VERSION 5.7 ;
  NOWIREEXTENSIONATPIN ON ;
  DIVIDERCHAR "/" ;
  BUSBITCHARS "[]" ;
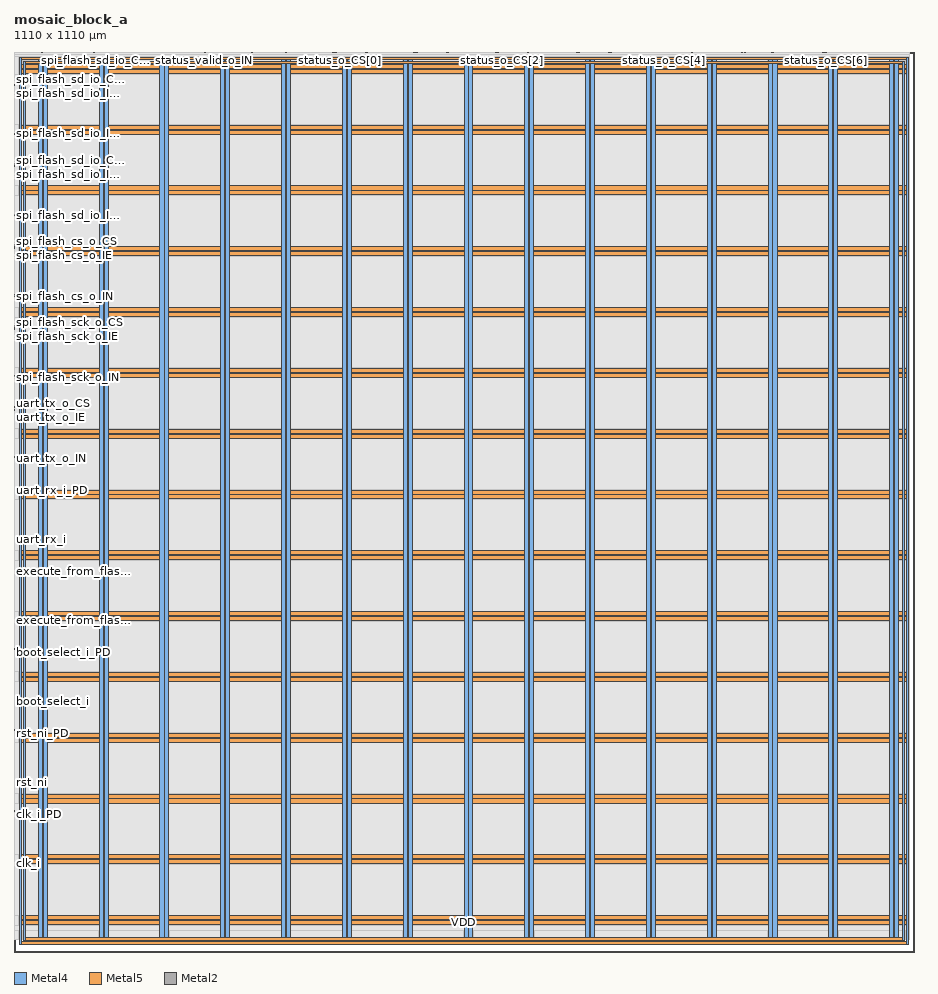
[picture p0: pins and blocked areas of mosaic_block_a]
MACRO mosaic_block_a
  CLASS BLOCK ;
  FOREIGN mosaic_block_a ;
  ORIGIN 0.000 0.000 ;
  SIZE 1110.000 BY 1110.000 ;
  PIN VDD
    DIRECTION INOUT ;
    USE POWER ;
    PORT
      LAYER Metal4 ;
        RECT 11.240 14.600 14.240 1098.680 ;
    END
    PORT
      LAYER Metal4 ;
        RECT 1095.680 14.600 1098.680 1098.680 ;
    END
    PORT
      LAYER Metal5 ;
        RECT 11.240 14.600 1098.680 17.600 ;
    END
    PORT
      LAYER Metal5 ;
        RECT 11.240 1095.680 1098.680 1098.680 ;
    END
    PORT
      LAYER Metal4 ;
        RECT 30.060 9.600 35.060 1103.680 ;
    END
    PORT
      LAYER Metal4 ;
        RECT 105.060 9.600 110.060 1103.680 ;
    END
    PORT
      LAYER Metal4 ;
        RECT 180.060 9.600 185.060 1103.680 ;
    END
    PORT
      LAYER Metal4 ;
        RECT 255.060 9.600 260.060 1103.680 ;
    END
    PORT
      LAYER Metal4 ;
        RECT 330.060 9.600 335.060 1103.680 ;
    END
    PORT
      LAYER Metal4 ;
        RECT 405.060 9.600 410.060 1103.680 ;
    END
    PORT
      LAYER Metal4 ;
        RECT 480.060 9.600 485.060 1103.680 ;
    END
    PORT
      LAYER Metal4 ;
        RECT 555.060 9.600 560.060 1103.680 ;
    END
    PORT
      LAYER Metal4 ;
        RECT 630.060 9.600 635.060 1103.680 ;
    END
    PORT
      LAYER Metal4 ;
        RECT 705.060 9.600 710.060 1103.680 ;
    END
    PORT
      LAYER Metal4 ;
        RECT 780.060 9.600 785.060 1103.680 ;
    END
    PORT
      LAYER Metal4 ;
        RECT 855.060 9.600 860.060 1103.680 ;
    END
    PORT
      LAYER Metal4 ;
        RECT 930.060 9.600 935.060 1103.680 ;
    END
    PORT
      LAYER Metal4 ;
        RECT 1005.060 9.600 1010.060 1103.680 ;
    END
    PORT
      LAYER Metal4 ;
        RECT 1080.060 9.600 1085.060 1103.680 ;
    END
    PORT
      LAYER Metal5 ;
        RECT 6.240 33.750 1103.680 38.750 ;
    END
    PORT
      LAYER Metal5 ;
        RECT 6.240 108.750 1103.680 113.750 ;
    END
    PORT
      LAYER Metal5 ;
        RECT 6.240 183.750 1103.680 188.750 ;
    END
    PORT
      LAYER Metal5 ;
        RECT 6.240 258.750 1103.680 263.750 ;
    END
    PORT
      LAYER Metal5 ;
        RECT 6.240 333.750 1103.680 338.750 ;
    END
    PORT
      LAYER Metal5 ;
        RECT 6.240 408.750 1103.680 413.750 ;
    END
    PORT
      LAYER Metal5 ;
        RECT 6.240 483.750 1103.680 488.750 ;
    END
    PORT
      LAYER Metal5 ;
        RECT 6.240 558.750 1103.680 563.750 ;
    END
    PORT
      LAYER Metal5 ;
        RECT 6.240 633.750 1103.680 638.750 ;
    END
    PORT
      LAYER Metal5 ;
        RECT 6.240 708.750 1103.680 713.750 ;
    END
    PORT
      LAYER Metal5 ;
        RECT 6.240 783.750 1103.680 788.750 ;
    END
    PORT
      LAYER Metal5 ;
        RECT 6.240 858.750 1103.680 863.750 ;
    END
    PORT
      LAYER Metal5 ;
        RECT 6.240 933.750 1103.680 938.750 ;
    END
    PORT
      LAYER Metal5 ;
        RECT 6.240 1008.750 1103.680 1013.750 ;
    END
    PORT
      LAYER Metal5 ;
        RECT 6.240 1083.750 1103.680 1088.750 ;
    END
  END VDD
  PIN VSS
    DIRECTION INOUT ;
    USE GROUND ;
    PORT
      LAYER Metal4 ;
        RECT 6.240 9.600 9.240 1103.680 ;
    END
    PORT
      LAYER Metal4 ;
        RECT 1100.680 9.600 1103.680 1103.680 ;
    END
    PORT
      LAYER Metal5 ;
        RECT 6.240 9.600 1103.680 12.600 ;
    END
    PORT
      LAYER Metal5 ;
        RECT 6.240 1100.680 1103.680 1103.680 ;
    END
    PORT
      LAYER Metal4 ;
        RECT 36.060 9.600 41.060 1103.680 ;
    END
    PORT
      LAYER Metal4 ;
        RECT 111.060 9.600 116.060 1103.680 ;
    END
    PORT
      LAYER Metal4 ;
        RECT 186.060 9.600 191.060 1103.680 ;
    END
    PORT
      LAYER Metal4 ;
        RECT 261.060 9.600 266.060 1103.680 ;
    END
    PORT
      LAYER Metal4 ;
        RECT 336.060 9.600 341.060 1103.680 ;
    END
    PORT
      LAYER Metal4 ;
        RECT 411.060 9.600 416.060 1103.680 ;
    END
    PORT
      LAYER Metal4 ;
        RECT 486.060 9.600 491.060 1103.680 ;
    END
    PORT
      LAYER Metal4 ;
        RECT 561.060 9.600 566.060 1103.680 ;
    END
    PORT
      LAYER Metal4 ;
        RECT 636.060 9.600 641.060 1103.680 ;
    END
    PORT
      LAYER Metal4 ;
        RECT 711.060 9.600 716.060 1103.680 ;
    END
    PORT
      LAYER Metal4 ;
        RECT 786.060 9.600 791.060 1103.680 ;
    END
    PORT
      LAYER Metal4 ;
        RECT 861.060 9.600 866.060 1103.680 ;
    END
    PORT
      LAYER Metal4 ;
        RECT 936.060 9.600 941.060 1103.680 ;
    END
    PORT
      LAYER Metal4 ;
        RECT 1011.060 9.600 1016.060 1103.680 ;
    END
    PORT
      LAYER Metal4 ;
        RECT 1086.060 9.600 1091.060 1103.680 ;
    END
    PORT
      LAYER Metal5 ;
        RECT 6.240 39.750 1103.680 44.750 ;
    END
    PORT
      LAYER Metal5 ;
        RECT 6.240 114.750 1103.680 119.750 ;
    END
    PORT
      LAYER Metal5 ;
        RECT 6.240 189.750 1103.680 194.750 ;
    END
    PORT
      LAYER Metal5 ;
        RECT 6.240 264.750 1103.680 269.750 ;
    END
    PORT
      LAYER Metal5 ;
        RECT 6.240 339.750 1103.680 344.750 ;
    END
    PORT
      LAYER Metal5 ;
        RECT 6.240 414.750 1103.680 419.750 ;
    END
    PORT
      LAYER Metal5 ;
        RECT 6.240 489.750 1103.680 494.750 ;
    END
    PORT
      LAYER Metal5 ;
        RECT 6.240 564.750 1103.680 569.750 ;
    END
    PORT
      LAYER Metal5 ;
        RECT 6.240 639.750 1103.680 644.750 ;
    END
    PORT
      LAYER Metal5 ;
        RECT 6.240 714.750 1103.680 719.750 ;
    END
    PORT
      LAYER Metal5 ;
        RECT 6.240 789.750 1103.680 794.750 ;
    END
    PORT
      LAYER Metal5 ;
        RECT 6.240 864.750 1103.680 869.750 ;
    END
    PORT
      LAYER Metal5 ;
        RECT 6.240 939.750 1103.680 944.750 ;
    END
    PORT
      LAYER Metal5 ;
        RECT 6.240 1014.750 1103.680 1019.750 ;
    END
    PORT
      LAYER Metal5 ;
        RECT 6.240 1089.750 1103.680 1094.750 ;
    END
  END VSS
  PIN boot_select_i
    DIRECTION INPUT ;
    USE SIGNAL ;
    ANTENNAGATEAREA 0.396000 ;
    PORT
      LAYER Metal2 ;
        RECT 0.000 308.760 1.000 309.140 ;
    END
  END boot_select_i
  PIN boot_select_i_PD
    DIRECTION OUTPUT ;
    USE SIGNAL ;
    ANTENNADIFFAREA 0.360800 ;
    PORT
      LAYER Metal2 ;
        RECT 0.000 369.290 1.000 369.670 ;
    END
  END boot_select_i_PD
  PIN boot_select_i_PU
    DIRECTION OUTPUT ;
    USE SIGNAL ;
    ANTENNADIFFAREA 0.360800 ;
    PORT
      LAYER Metal2 ;
        RECT 0.000 373.655 1.000 374.035 ;
    END
  END boot_select_i_PU
  PIN clk_i
    DIRECTION INPUT ;
    USE SIGNAL ;
    ANTENNAGATEAREA 9.476000 ;
    PORT
      LAYER Metal2 ;
        RECT 0.000 108.760 1.000 109.140 ;
    END
  END clk_i
  PIN clk_i_PD
    DIRECTION OUTPUT ;
    USE SIGNAL ;
    ANTENNADIFFAREA 0.360800 ;
    PORT
      LAYER Metal2 ;
        RECT 0.000 169.290 1.000 169.670 ;
    END
  END clk_i_PD
  PIN clk_i_PU
    DIRECTION OUTPUT ;
    USE SIGNAL ;
    ANTENNADIFFAREA 0.360800 ;
    PORT
      LAYER Metal2 ;
        RECT 0.000 173.655 1.000 174.035 ;
    END
  END clk_i_PU
  PIN execute_from_flash_i
    DIRECTION INPUT ;
    USE SIGNAL ;
    ANTENNAGATEAREA 0.498500 ;
    PORT
      LAYER Metal2 ;
        RECT 0.000 408.760 1.000 409.140 ;
    END
  END execute_from_flash_i
  PIN execute_from_flash_i_PD
    DIRECTION OUTPUT ;
    USE SIGNAL ;
    ANTENNADIFFAREA 0.360800 ;
    PORT
      LAYER Metal2 ;
        RECT 0.000 469.290 1.000 469.670 ;
    END
  END execute_from_flash_i_PD
  PIN execute_from_flash_i_PU
    DIRECTION OUTPUT ;
    USE SIGNAL ;
    ANTENNADIFFAREA 0.360800 ;
    PORT
      LAYER Metal2 ;
        RECT 0.000 473.655 1.000 474.035 ;
    END
  END execute_from_flash_i_PU
  PIN rst_ni
    DIRECTION INPUT ;
    USE SIGNAL ;
    ANTENNAGATEAREA 0.396000 ;
    PORT
      LAYER Metal2 ;
        RECT 0.000 208.760 1.000 209.140 ;
    END
  END rst_ni
  PIN rst_ni_PD
    DIRECTION OUTPUT ;
    USE SIGNAL ;
    ANTENNADIFFAREA 0.536800 ;
    PORT
      LAYER Metal2 ;
        RECT 0.000 269.290 1.000 269.670 ;
    END
  END rst_ni_PD
  PIN rst_ni_PU
    DIRECTION OUTPUT ;
    USE SIGNAL ;
    ANTENNADIFFAREA 0.360800 ;
    PORT
      LAYER Metal2 ;
        RECT 0.000 273.655 1.000 274.035 ;
    END
  END rst_ni_PU
  PIN spi_flash_cs_o_CS
    DIRECTION OUTPUT ;
    USE SIGNAL ;
    ANTENNADIFFAREA 0.360800 ;
    PORT
      LAYER Metal2 ;
        RECT 0.000 876.260 1.000 876.640 ;
    END
  END spi_flash_cs_o_CS
  PIN spi_flash_cs_o_IE
    DIRECTION OUTPUT ;
    USE SIGNAL ;
    ANTENNADIFFAREA 0.360800 ;
    PORT
      LAYER Metal2 ;
        RECT 0.000 868.235 1.000 868.615 ;
    END
  END spi_flash_cs_o_IE
  PIN spi_flash_cs_o_IN
    DIRECTION INPUT ;
    USE SIGNAL ;
    PORT
      LAYER Metal2 ;
        RECT 0.000 808.760 1.000 809.140 ;
    END
  END spi_flash_cs_o_IN
  PIN spi_flash_cs_o_OE
    DIRECTION OUTPUT ;
    USE SIGNAL ;
    ANTENNADIFFAREA 0.536800 ;
    PORT
      LAYER Metal2 ;
        RECT 0.000 809.490 1.000 809.870 ;
    END
  END spi_flash_cs_o_OE
  PIN spi_flash_cs_o_OUT
    DIRECTION OUTPUT ;
    USE SIGNAL ;
    ANTENNADIFFAREA 0.897600 ;
    PORT
      LAYER Metal2 ;
        RECT 0.000 810.220 1.000 810.600 ;
    END
  END spi_flash_cs_o_OUT
  PIN spi_flash_cs_o_PD
    DIRECTION OUTPUT ;
    USE SIGNAL ;
    ANTENNADIFFAREA 0.360800 ;
    PORT
      LAYER Metal2 ;
        RECT 0.000 869.290 1.000 869.670 ;
    END
  END spi_flash_cs_o_PD
  PIN spi_flash_cs_o_PDRV0
    DIRECTION OUTPUT ;
    USE SIGNAL ;
    ANTENNADIFFAREA 0.360800 ;
    PORT
      LAYER Metal2 ;
        RECT 0.000 872.510 1.000 872.890 ;
    END
  END spi_flash_cs_o_PDRV0
  PIN spi_flash_cs_o_PDRV1
    DIRECTION OUTPUT ;
    USE SIGNAL ;
    ANTENNADIFFAREA 0.536800 ;
    PORT
      LAYER Metal2 ;
        RECT 0.000 871.800 1.000 872.180 ;
    END
  END spi_flash_cs_o_PDRV1
  PIN spi_flash_cs_o_PU
    DIRECTION OUTPUT ;
    USE SIGNAL ;
    ANTENNADIFFAREA 0.360800 ;
    PORT
      LAYER Metal2 ;
        RECT 0.000 873.655 1.000 874.035 ;
    END
  END spi_flash_cs_o_PU
  PIN spi_flash_cs_o_SL
    DIRECTION OUTPUT ;
    USE SIGNAL ;
    ANTENNADIFFAREA 0.360800 ;
    PORT
      LAYER Metal2 ;
        RECT 0.000 810.950 1.000 811.330 ;
    END
  END spi_flash_cs_o_SL
  PIN spi_flash_sck_o_CS
    DIRECTION OUTPUT ;
    USE SIGNAL ;
    ANTENNADIFFAREA 0.360800 ;
    PORT
      LAYER Metal2 ;
        RECT 0.000 776.260 1.000 776.640 ;
    END
  END spi_flash_sck_o_CS
  PIN spi_flash_sck_o_IE
    DIRECTION OUTPUT ;
    USE SIGNAL ;
    ANTENNADIFFAREA 0.360800 ;
    PORT
      LAYER Metal2 ;
        RECT 0.000 768.235 1.000 768.615 ;
    END
  END spi_flash_sck_o_IE
  PIN spi_flash_sck_o_IN
    DIRECTION INPUT ;
    USE SIGNAL ;
    PORT
      LAYER Metal2 ;
        RECT 0.000 708.760 1.000 709.140 ;
    END
  END spi_flash_sck_o_IN
  PIN spi_flash_sck_o_OE
    DIRECTION OUTPUT ;
    USE SIGNAL ;
    ANTENNADIFFAREA 0.536800 ;
    PORT
      LAYER Metal2 ;
        RECT 0.000 709.490 1.000 709.870 ;
    END
  END spi_flash_sck_o_OE
  PIN spi_flash_sck_o_OUT
    DIRECTION OUTPUT ;
    USE SIGNAL ;
    ANTENNADIFFAREA 0.897600 ;
    PORT
      LAYER Metal2 ;
        RECT 0.000 710.220 1.000 710.600 ;
    END
  END spi_flash_sck_o_OUT
  PIN spi_flash_sck_o_PD
    DIRECTION OUTPUT ;
    USE SIGNAL ;
    ANTENNADIFFAREA 0.360800 ;
    PORT
      LAYER Metal2 ;
        RECT 0.000 769.290 1.000 769.670 ;
    END
  END spi_flash_sck_o_PD
  PIN spi_flash_sck_o_PDRV0
    DIRECTION OUTPUT ;
    USE SIGNAL ;
    ANTENNADIFFAREA 0.360800 ;
    PORT
      LAYER Metal2 ;
        RECT 0.000 772.510 1.000 772.890 ;
    END
  END spi_flash_sck_o_PDRV0
  PIN spi_flash_sck_o_PDRV1
    DIRECTION OUTPUT ;
    USE SIGNAL ;
    ANTENNADIFFAREA 0.536800 ;
    PORT
      LAYER Metal2 ;
        RECT 0.000 771.800 1.000 772.180 ;
    END
  END spi_flash_sck_o_PDRV1
  PIN spi_flash_sck_o_PU
    DIRECTION OUTPUT ;
    USE SIGNAL ;
    ANTENNADIFFAREA 0.360800 ;
    PORT
      LAYER Metal2 ;
        RECT 0.000 773.655 1.000 774.035 ;
    END
  END spi_flash_sck_o_PU
  PIN spi_flash_sck_o_SL
    DIRECTION OUTPUT ;
    USE SIGNAL ;
    ANTENNADIFFAREA 0.360800 ;
    PORT
      LAYER Metal2 ;
        RECT 0.000 710.950 1.000 711.330 ;
    END
  END spi_flash_sck_o_SL
  PIN spi_flash_sd_io_CS[0]
    DIRECTION OUTPUT ;
    USE SIGNAL ;
    ANTENNADIFFAREA 0.360800 ;
    PORT
      LAYER Metal2 ;
        RECT 0.000 976.260 1.000 976.640 ;
    END
  END spi_flash_sd_io_CS[0]
  PIN spi_flash_sd_io_CS[1]
    DIRECTION OUTPUT ;
    USE SIGNAL ;
    ANTENNADIFFAREA 0.360800 ;
    PORT
      LAYER Metal2 ;
        RECT 0.000 1076.260 1.000 1076.640 ;
    END
  END spi_flash_sd_io_CS[1]
  PIN spi_flash_sd_io_CS[2]
    DIRECTION OUTPUT ;
    USE SIGNAL ;
    ANTENNADIFFAREA 0.360800 ;
    PORT
      LAYER Metal2 ;
        RECT 101.260 1109.000 101.640 1110.000 ;
    END
  END spi_flash_sd_io_CS[2]
  PIN spi_flash_sd_io_CS[3]
    DIRECTION OUTPUT ;
    USE SIGNAL ;
    ANTENNADIFFAREA 0.360800 ;
    PORT
      LAYER Metal2 ;
        RECT 201.260 1109.000 201.640 1110.000 ;
    END
  END spi_flash_sd_io_CS[3]
  PIN spi_flash_sd_io_IE[0]
    DIRECTION OUTPUT ;
    USE SIGNAL ;
    ANTENNADIFFAREA 0.897600 ;
    PORT
      LAYER Metal2 ;
        RECT 0.000 968.235 1.000 968.615 ;
    END
  END spi_flash_sd_io_IE[0]
  PIN spi_flash_sd_io_IE[1]
    DIRECTION OUTPUT ;
    USE SIGNAL ;
    ANTENNADIFFAREA 0.897600 ;
    PORT
      LAYER Metal2 ;
        RECT 0.000 1068.235 1.000 1068.615 ;
    END
  END spi_flash_sd_io_IE[1]
  PIN spi_flash_sd_io_IE[2]
    DIRECTION OUTPUT ;
    USE SIGNAL ;
    ANTENNADIFFAREA 0.897600 ;
    PORT
      LAYER Metal2 ;
        RECT 93.235 1109.000 93.615 1110.000 ;
    END
  END spi_flash_sd_io_IE[2]
  PIN spi_flash_sd_io_IE[3]
    DIRECTION OUTPUT ;
    USE SIGNAL ;
    ANTENNADIFFAREA 0.897600 ;
    PORT
      LAYER Metal2 ;
        RECT 193.235 1109.000 193.615 1110.000 ;
    END
  END spi_flash_sd_io_IE[3]
  PIN spi_flash_sd_io_IN[0]
    DIRECTION INPUT ;
    USE SIGNAL ;
    ANTENNAGATEAREA 0.396000 ;
    PORT
      LAYER Metal2 ;
        RECT 0.000 908.760 1.000 909.140 ;
    END
  END spi_flash_sd_io_IN[0]
  PIN spi_flash_sd_io_IN[1]
    DIRECTION INPUT ;
    USE SIGNAL ;
    ANTENNAGATEAREA 0.498500 ;
    PORT
      LAYER Metal2 ;
        RECT 0.000 1008.760 1.000 1009.140 ;
    END
  END spi_flash_sd_io_IN[1]
  PIN spi_flash_sd_io_IN[2]
    DIRECTION INPUT ;
    USE SIGNAL ;
    ANTENNAGATEAREA 0.396000 ;
    PORT
      LAYER Metal2 ;
        RECT 33.760 1109.000 34.140 1110.000 ;
    END
  END spi_flash_sd_io_IN[2]
  PIN spi_flash_sd_io_IN[3]
    DIRECTION INPUT ;
    USE SIGNAL ;
    ANTENNAGATEAREA 0.396000 ;
    PORT
      LAYER Metal2 ;
        RECT 133.760 1109.000 134.140 1110.000 ;
    END
  END spi_flash_sd_io_IN[3]
  PIN spi_flash_sd_io_OE[0]
    DIRECTION OUTPUT ;
    USE SIGNAL ;
    ANTENNADIFFAREA 0.897600 ;
    PORT
      LAYER Metal2 ;
        RECT 0.000 909.490 1.000 909.870 ;
    END
  END spi_flash_sd_io_OE[0]
  PIN spi_flash_sd_io_OE[1]
    DIRECTION OUTPUT ;
    USE SIGNAL ;
    ANTENNADIFFAREA 0.897600 ;
    PORT
      LAYER Metal2 ;
        RECT 0.000 1009.490 1.000 1009.870 ;
    END
  END spi_flash_sd_io_OE[1]
  PIN spi_flash_sd_io_OE[2]
    DIRECTION OUTPUT ;
    USE SIGNAL ;
    ANTENNADIFFAREA 0.897600 ;
    PORT
      LAYER Metal2 ;
        RECT 34.490 1109.000 34.870 1110.000 ;
    END
  END spi_flash_sd_io_OE[2]
  PIN spi_flash_sd_io_OE[3]
    DIRECTION OUTPUT ;
    USE SIGNAL ;
    ANTENNADIFFAREA 0.897600 ;
    PORT
      LAYER Metal2 ;
        RECT 134.490 1109.000 134.870 1110.000 ;
    END
  END spi_flash_sd_io_OE[3]
  PIN spi_flash_sd_io_OUT[0]
    DIRECTION OUTPUT ;
    USE SIGNAL ;
    ANTENNADIFFAREA 0.897600 ;
    PORT
      LAYER Metal2 ;
        RECT 0.000 910.220 1.000 910.600 ;
    END
  END spi_flash_sd_io_OUT[0]
  PIN spi_flash_sd_io_OUT[1]
    DIRECTION OUTPUT ;
    USE SIGNAL ;
    ANTENNADIFFAREA 0.897600 ;
    PORT
      LAYER Metal2 ;
        RECT 0.000 1010.220 1.000 1010.600 ;
    END
  END spi_flash_sd_io_OUT[1]
  PIN spi_flash_sd_io_OUT[2]
    DIRECTION OUTPUT ;
    USE SIGNAL ;
    ANTENNADIFFAREA 0.897600 ;
    PORT
      LAYER Metal2 ;
        RECT 35.220 1109.000 35.600 1110.000 ;
    END
  END spi_flash_sd_io_OUT[2]
  PIN spi_flash_sd_io_OUT[3]
    DIRECTION OUTPUT ;
    USE SIGNAL ;
    ANTENNADIFFAREA 0.897600 ;
    PORT
      LAYER Metal2 ;
        RECT 135.220 1109.000 135.600 1110.000 ;
    END
  END spi_flash_sd_io_OUT[3]
  PIN spi_flash_sd_io_PDRV0[0]
    DIRECTION OUTPUT ;
    USE SIGNAL ;
    ANTENNADIFFAREA 0.360800 ;
    PORT
      LAYER Metal2 ;
        RECT 0.000 972.510 1.000 972.890 ;
    END
  END spi_flash_sd_io_PDRV0[0]
  PIN spi_flash_sd_io_PDRV0[1]
    DIRECTION OUTPUT ;
    USE SIGNAL ;
    ANTENNADIFFAREA 0.360800 ;
    PORT
      LAYER Metal2 ;
        RECT 0.000 1072.510 1.000 1072.890 ;
    END
  END spi_flash_sd_io_PDRV0[1]
  PIN spi_flash_sd_io_PDRV0[2]
    DIRECTION OUTPUT ;
    USE SIGNAL ;
    ANTENNADIFFAREA 0.360800 ;
    PORT
      LAYER Metal2 ;
        RECT 97.510 1109.000 97.890 1110.000 ;
    END
  END spi_flash_sd_io_PDRV0[2]
  PIN spi_flash_sd_io_PDRV0[3]
    DIRECTION OUTPUT ;
    USE SIGNAL ;
    ANTENNADIFFAREA 0.360800 ;
    PORT
      LAYER Metal2 ;
        RECT 197.510 1109.000 197.890 1110.000 ;
    END
  END spi_flash_sd_io_PDRV0[3]
  PIN spi_flash_sd_io_PDRV1[0]
    DIRECTION OUTPUT ;
    USE SIGNAL ;
    ANTENNADIFFAREA 0.536800 ;
    PORT
      LAYER Metal2 ;
        RECT 0.000 971.800 1.000 972.180 ;
    END
  END spi_flash_sd_io_PDRV1[0]
  PIN spi_flash_sd_io_PDRV1[1]
    DIRECTION OUTPUT ;
    USE SIGNAL ;
    ANTENNADIFFAREA 0.536800 ;
    PORT
      LAYER Metal2 ;
        RECT 0.000 1071.800 1.000 1072.180 ;
    END
  END spi_flash_sd_io_PDRV1[1]
  PIN spi_flash_sd_io_PDRV1[2]
    DIRECTION OUTPUT ;
    USE SIGNAL ;
    ANTENNADIFFAREA 0.536800 ;
    PORT
      LAYER Metal2 ;
        RECT 96.800 1109.000 97.180 1110.000 ;
    END
  END spi_flash_sd_io_PDRV1[2]
  PIN spi_flash_sd_io_PDRV1[3]
    DIRECTION OUTPUT ;
    USE SIGNAL ;
    ANTENNADIFFAREA 0.536800 ;
    PORT
      LAYER Metal2 ;
        RECT 196.800 1109.000 197.180 1110.000 ;
    END
  END spi_flash_sd_io_PDRV1[3]
  PIN spi_flash_sd_io_PD[0]
    DIRECTION OUTPUT ;
    USE SIGNAL ;
    ANTENNADIFFAREA 0.360800 ;
    PORT
      LAYER Metal2 ;
        RECT 0.000 969.290 1.000 969.670 ;
    END
  END spi_flash_sd_io_PD[0]
  PIN spi_flash_sd_io_PD[1]
    DIRECTION OUTPUT ;
    USE SIGNAL ;
    ANTENNADIFFAREA 0.360800 ;
    PORT
      LAYER Metal2 ;
        RECT 0.000 1069.290 1.000 1069.670 ;
    END
  END spi_flash_sd_io_PD[1]
  PIN spi_flash_sd_io_PD[2]
    DIRECTION OUTPUT ;
    USE SIGNAL ;
    ANTENNADIFFAREA 0.360800 ;
    PORT
      LAYER Metal2 ;
        RECT 94.290 1109.000 94.670 1110.000 ;
    END
  END spi_flash_sd_io_PD[2]
  PIN spi_flash_sd_io_PD[3]
    DIRECTION OUTPUT ;
    USE SIGNAL ;
    ANTENNADIFFAREA 0.360800 ;
    PORT
      LAYER Metal2 ;
        RECT 194.290 1109.000 194.670 1110.000 ;
    END
  END spi_flash_sd_io_PD[3]
  PIN spi_flash_sd_io_PU[0]
    DIRECTION OUTPUT ;
    USE SIGNAL ;
    ANTENNADIFFAREA 0.360800 ;
    PORT
      LAYER Metal2 ;
        RECT 0.000 973.655 1.000 974.035 ;
    END
  END spi_flash_sd_io_PU[0]
  PIN spi_flash_sd_io_PU[1]
    DIRECTION OUTPUT ;
    USE SIGNAL ;
    ANTENNADIFFAREA 0.360800 ;
    PORT
      LAYER Metal2 ;
        RECT 0.000 1073.655 1.000 1074.035 ;
    END
  END spi_flash_sd_io_PU[1]
  PIN spi_flash_sd_io_PU[2]
    DIRECTION OUTPUT ;
    USE SIGNAL ;
    ANTENNADIFFAREA 0.360800 ;
    PORT
      LAYER Metal2 ;
        RECT 98.655 1109.000 99.035 1110.000 ;
    END
  END spi_flash_sd_io_PU[2]
  PIN spi_flash_sd_io_PU[3]
    DIRECTION OUTPUT ;
    USE SIGNAL ;
    ANTENNADIFFAREA 0.360800 ;
    PORT
      LAYER Metal2 ;
        RECT 198.655 1109.000 199.035 1110.000 ;
    END
  END spi_flash_sd_io_PU[3]
  PIN spi_flash_sd_io_SL[0]
    DIRECTION OUTPUT ;
    USE SIGNAL ;
    ANTENNADIFFAREA 0.360800 ;
    PORT
      LAYER Metal2 ;
        RECT 0.000 910.950 1.000 911.330 ;
    END
  END spi_flash_sd_io_SL[0]
  PIN spi_flash_sd_io_SL[1]
    DIRECTION OUTPUT ;
    USE SIGNAL ;
    ANTENNADIFFAREA 0.360800 ;
    PORT
      LAYER Metal2 ;
        RECT 0.000 1010.950 1.000 1011.330 ;
    END
  END spi_flash_sd_io_SL[1]
  PIN spi_flash_sd_io_SL[2]
    DIRECTION OUTPUT ;
    USE SIGNAL ;
    ANTENNADIFFAREA 0.360800 ;
    PORT
      LAYER Metal2 ;
        RECT 35.950 1109.000 36.330 1110.000 ;
    END
  END spi_flash_sd_io_SL[2]
  PIN spi_flash_sd_io_SL[3]
    DIRECTION OUTPUT ;
    USE SIGNAL ;
    ANTENNADIFFAREA 0.360800 ;
    PORT
      LAYER Metal2 ;
        RECT 135.950 1109.000 136.330 1110.000 ;
    END
  END spi_flash_sd_io_SL[3]
  PIN status_o_CS[0]
    DIRECTION OUTPUT ;
    USE SIGNAL ;
    ANTENNADIFFAREA 0.360800 ;
    PORT
      LAYER Metal2 ;
        RECT 401.260 1109.000 401.640 1110.000 ;
    END
  END status_o_CS[0]
  PIN status_o_CS[1]
    DIRECTION OUTPUT ;
    USE SIGNAL ;
    ANTENNADIFFAREA 0.360800 ;
    PORT
      LAYER Metal2 ;
        RECT 501.260 1109.000 501.640 1110.000 ;
    END
  END status_o_CS[1]
  PIN status_o_CS[2]
    DIRECTION OUTPUT ;
    USE SIGNAL ;
    ANTENNADIFFAREA 0.360800 ;
    PORT
      LAYER Metal2 ;
        RECT 601.260 1109.000 601.640 1110.000 ;
    END
  END status_o_CS[2]
  PIN status_o_CS[3]
    DIRECTION OUTPUT ;
    USE SIGNAL ;
    ANTENNADIFFAREA 0.360800 ;
    PORT
      LAYER Metal2 ;
        RECT 701.260 1109.000 701.640 1110.000 ;
    END
  END status_o_CS[3]
  PIN status_o_CS[4]
    DIRECTION OUTPUT ;
    USE SIGNAL ;
    ANTENNADIFFAREA 0.360800 ;
    PORT
      LAYER Metal2 ;
        RECT 801.260 1109.000 801.640 1110.000 ;
    END
  END status_o_CS[4]
  PIN status_o_CS[5]
    DIRECTION OUTPUT ;
    USE SIGNAL ;
    ANTENNADIFFAREA 0.360800 ;
    PORT
      LAYER Metal2 ;
        RECT 901.260 1109.000 901.640 1110.000 ;
    END
  END status_o_CS[5]
  PIN status_o_CS[6]
    DIRECTION OUTPUT ;
    USE SIGNAL ;
    ANTENNADIFFAREA 0.360800 ;
    PORT
      LAYER Metal2 ;
        RECT 1001.260 1109.000 1001.640 1110.000 ;
    END
  END status_o_CS[6]
  PIN status_o_IE[0]
    DIRECTION OUTPUT ;
    USE SIGNAL ;
    ANTENNADIFFAREA 0.360800 ;
    PORT
      LAYER Metal2 ;
        RECT 393.235 1109.000 393.615 1110.000 ;
    END
  END status_o_IE[0]
  PIN status_o_IE[1]
    DIRECTION OUTPUT ;
    USE SIGNAL ;
    ANTENNADIFFAREA 0.360800 ;
    PORT
      LAYER Metal2 ;
        RECT 493.235 1109.000 493.615 1110.000 ;
    END
  END status_o_IE[1]
  PIN status_o_IE[2]
    DIRECTION OUTPUT ;
    USE SIGNAL ;
    ANTENNADIFFAREA 0.360800 ;
    PORT
      LAYER Metal2 ;
        RECT 593.235 1109.000 593.615 1110.000 ;
    END
  END status_o_IE[2]
  PIN status_o_IE[3]
    DIRECTION OUTPUT ;
    USE SIGNAL ;
    ANTENNADIFFAREA 0.360800 ;
    PORT
      LAYER Metal2 ;
        RECT 693.235 1109.000 693.615 1110.000 ;
    END
  END status_o_IE[3]
  PIN status_o_IE[4]
    DIRECTION OUTPUT ;
    USE SIGNAL ;
    ANTENNADIFFAREA 0.360800 ;
    PORT
      LAYER Metal2 ;
        RECT 793.235 1109.000 793.615 1110.000 ;
    END
  END status_o_IE[4]
  PIN status_o_IE[5]
    DIRECTION OUTPUT ;
    USE SIGNAL ;
    ANTENNADIFFAREA 0.360800 ;
    PORT
      LAYER Metal2 ;
        RECT 893.235 1109.000 893.615 1110.000 ;
    END
  END status_o_IE[5]
  PIN status_o_IE[6]
    DIRECTION OUTPUT ;
    USE SIGNAL ;
    ANTENNADIFFAREA 0.360800 ;
    PORT
      LAYER Metal2 ;
        RECT 993.235 1109.000 993.615 1110.000 ;
    END
  END status_o_IE[6]
  PIN status_o_IN[0]
    DIRECTION INPUT ;
    USE SIGNAL ;
    PORT
      LAYER Metal2 ;
        RECT 333.760 1109.000 334.140 1110.000 ;
    END
  END status_o_IN[0]
  PIN status_o_IN[1]
    DIRECTION INPUT ;
    USE SIGNAL ;
    PORT
      LAYER Metal2 ;
        RECT 433.760 1109.000 434.140 1110.000 ;
    END
  END status_o_IN[1]
  PIN status_o_IN[2]
    DIRECTION INPUT ;
    USE SIGNAL ;
    PORT
      LAYER Metal2 ;
        RECT 533.760 1109.000 534.140 1110.000 ;
    END
  END status_o_IN[2]
  PIN status_o_IN[3]
    DIRECTION INPUT ;
    USE SIGNAL ;
    PORT
      LAYER Metal2 ;
        RECT 633.760 1109.000 634.140 1110.000 ;
    END
  END status_o_IN[3]
  PIN status_o_IN[4]
    DIRECTION INPUT ;
    USE SIGNAL ;
    PORT
      LAYER Metal2 ;
        RECT 733.760 1109.000 734.140 1110.000 ;
    END
  END status_o_IN[4]
  PIN status_o_IN[5]
    DIRECTION INPUT ;
    USE SIGNAL ;
    PORT
      LAYER Metal2 ;
        RECT 833.760 1109.000 834.140 1110.000 ;
    END
  END status_o_IN[5]
  PIN status_o_IN[6]
    DIRECTION INPUT ;
    USE SIGNAL ;
    PORT
      LAYER Metal2 ;
        RECT 933.760 1109.000 934.140 1110.000 ;
    END
  END status_o_IN[6]
  PIN status_o_OE[0]
    DIRECTION OUTPUT ;
    USE SIGNAL ;
    ANTENNADIFFAREA 0.536800 ;
    PORT
      LAYER Metal2 ;
        RECT 334.490 1109.000 334.870 1110.000 ;
    END
  END status_o_OE[0]
  PIN status_o_OE[1]
    DIRECTION OUTPUT ;
    USE SIGNAL ;
    ANTENNADIFFAREA 0.536800 ;
    PORT
      LAYER Metal2 ;
        RECT 434.490 1109.000 434.870 1110.000 ;
    END
  END status_o_OE[1]
  PIN status_o_OE[2]
    DIRECTION OUTPUT ;
    USE SIGNAL ;
    ANTENNADIFFAREA 0.536800 ;
    PORT
      LAYER Metal2 ;
        RECT 534.490 1109.000 534.870 1110.000 ;
    END
  END status_o_OE[2]
  PIN status_o_OE[3]
    DIRECTION OUTPUT ;
    USE SIGNAL ;
    ANTENNADIFFAREA 0.536800 ;
    PORT
      LAYER Metal2 ;
        RECT 634.490 1109.000 634.870 1110.000 ;
    END
  END status_o_OE[3]
  PIN status_o_OE[4]
    DIRECTION OUTPUT ;
    USE SIGNAL ;
    ANTENNADIFFAREA 0.536800 ;
    PORT
      LAYER Metal2 ;
        RECT 734.490 1109.000 734.870 1110.000 ;
    END
  END status_o_OE[4]
  PIN status_o_OE[5]
    DIRECTION OUTPUT ;
    USE SIGNAL ;
    ANTENNADIFFAREA 0.536800 ;
    PORT
      LAYER Metal2 ;
        RECT 834.490 1109.000 834.870 1110.000 ;
    END
  END status_o_OE[5]
  PIN status_o_OE[6]
    DIRECTION OUTPUT ;
    USE SIGNAL ;
    ANTENNADIFFAREA 0.536800 ;
    PORT
      LAYER Metal2 ;
        RECT 934.490 1109.000 934.870 1110.000 ;
    END
  END status_o_OE[6]
  PIN status_o_OUT[0]
    DIRECTION OUTPUT ;
    USE SIGNAL ;
    ANTENNADIFFAREA 0.897600 ;
    PORT
      LAYER Metal2 ;
        RECT 335.220 1109.000 335.600 1110.000 ;
    END
  END status_o_OUT[0]
  PIN status_o_OUT[1]
    DIRECTION OUTPUT ;
    USE SIGNAL ;
    ANTENNADIFFAREA 0.897600 ;
    PORT
      LAYER Metal2 ;
        RECT 435.220 1109.000 435.600 1110.000 ;
    END
  END status_o_OUT[1]
  PIN status_o_OUT[2]
    DIRECTION OUTPUT ;
    USE SIGNAL ;
    ANTENNADIFFAREA 0.897600 ;
    PORT
      LAYER Metal2 ;
        RECT 535.220 1109.000 535.600 1110.000 ;
    END
  END status_o_OUT[2]
  PIN status_o_OUT[3]
    DIRECTION OUTPUT ;
    USE SIGNAL ;
    ANTENNADIFFAREA 0.897600 ;
    PORT
      LAYER Metal2 ;
        RECT 635.220 1109.000 635.600 1110.000 ;
    END
  END status_o_OUT[3]
  PIN status_o_OUT[4]
    DIRECTION OUTPUT ;
    USE SIGNAL ;
    ANTENNADIFFAREA 0.897600 ;
    PORT
      LAYER Metal2 ;
        RECT 735.220 1109.000 735.600 1110.000 ;
    END
  END status_o_OUT[4]
  PIN status_o_OUT[5]
    DIRECTION OUTPUT ;
    USE SIGNAL ;
    ANTENNADIFFAREA 0.897600 ;
    PORT
      LAYER Metal2 ;
        RECT 835.220 1109.000 835.600 1110.000 ;
    END
  END status_o_OUT[5]
  PIN status_o_OUT[6]
    DIRECTION OUTPUT ;
    USE SIGNAL ;
    ANTENNADIFFAREA 0.897600 ;
    PORT
      LAYER Metal2 ;
        RECT 935.220 1109.000 935.600 1110.000 ;
    END
  END status_o_OUT[6]
  PIN status_o_PDRV0[0]
    DIRECTION OUTPUT ;
    USE SIGNAL ;
    ANTENNADIFFAREA 0.360800 ;
    PORT
      LAYER Metal2 ;
        RECT 397.510 1109.000 397.890 1110.000 ;
    END
  END status_o_PDRV0[0]
  PIN status_o_PDRV0[1]
    DIRECTION OUTPUT ;
    USE SIGNAL ;
    ANTENNADIFFAREA 0.360800 ;
    PORT
      LAYER Metal2 ;
        RECT 497.510 1109.000 497.890 1110.000 ;
    END
  END status_o_PDRV0[1]
  PIN status_o_PDRV0[2]
    DIRECTION OUTPUT ;
    USE SIGNAL ;
    ANTENNADIFFAREA 0.360800 ;
    PORT
      LAYER Metal2 ;
        RECT 597.510 1109.000 597.890 1110.000 ;
    END
  END status_o_PDRV0[2]
  PIN status_o_PDRV0[3]
    DIRECTION OUTPUT ;
    USE SIGNAL ;
    ANTENNADIFFAREA 0.360800 ;
    PORT
      LAYER Metal2 ;
        RECT 697.510 1109.000 697.890 1110.000 ;
    END
  END status_o_PDRV0[3]
  PIN status_o_PDRV0[4]
    DIRECTION OUTPUT ;
    USE SIGNAL ;
    ANTENNADIFFAREA 0.360800 ;
    PORT
      LAYER Metal2 ;
        RECT 797.510 1109.000 797.890 1110.000 ;
    END
  END status_o_PDRV0[4]
  PIN status_o_PDRV0[5]
    DIRECTION OUTPUT ;
    USE SIGNAL ;
    ANTENNADIFFAREA 0.360800 ;
    PORT
      LAYER Metal2 ;
        RECT 897.510 1109.000 897.890 1110.000 ;
    END
  END status_o_PDRV0[5]
  PIN status_o_PDRV0[6]
    DIRECTION OUTPUT ;
    USE SIGNAL ;
    ANTENNADIFFAREA 0.360800 ;
    PORT
      LAYER Metal2 ;
        RECT 997.510 1109.000 997.890 1110.000 ;
    END
  END status_o_PDRV0[6]
  PIN status_o_PDRV1[0]
    DIRECTION OUTPUT ;
    USE SIGNAL ;
    ANTENNADIFFAREA 0.536800 ;
    PORT
      LAYER Metal2 ;
        RECT 396.800 1109.000 397.180 1110.000 ;
    END
  END status_o_PDRV1[0]
  PIN status_o_PDRV1[1]
    DIRECTION OUTPUT ;
    USE SIGNAL ;
    ANTENNADIFFAREA 0.536800 ;
    PORT
      LAYER Metal2 ;
        RECT 496.800 1109.000 497.180 1110.000 ;
    END
  END status_o_PDRV1[1]
  PIN status_o_PDRV1[2]
    DIRECTION OUTPUT ;
    USE SIGNAL ;
    ANTENNADIFFAREA 0.536800 ;
    PORT
      LAYER Metal2 ;
        RECT 596.800 1109.000 597.180 1110.000 ;
    END
  END status_o_PDRV1[2]
  PIN status_o_PDRV1[3]
    DIRECTION OUTPUT ;
    USE SIGNAL ;
    ANTENNADIFFAREA 0.536800 ;
    PORT
      LAYER Metal2 ;
        RECT 696.800 1109.000 697.180 1110.000 ;
    END
  END status_o_PDRV1[3]
  PIN status_o_PDRV1[4]
    DIRECTION OUTPUT ;
    USE SIGNAL ;
    ANTENNADIFFAREA 0.536800 ;
    PORT
      LAYER Metal2 ;
        RECT 796.800 1109.000 797.180 1110.000 ;
    END
  END status_o_PDRV1[4]
  PIN status_o_PDRV1[5]
    DIRECTION OUTPUT ;
    USE SIGNAL ;
    ANTENNADIFFAREA 0.536800 ;
    PORT
      LAYER Metal2 ;
        RECT 896.800 1109.000 897.180 1110.000 ;
    END
  END status_o_PDRV1[5]
  PIN status_o_PDRV1[6]
    DIRECTION OUTPUT ;
    USE SIGNAL ;
    ANTENNADIFFAREA 0.536800 ;
    PORT
      LAYER Metal2 ;
        RECT 996.800 1109.000 997.180 1110.000 ;
    END
  END status_o_PDRV1[6]
  PIN status_o_PD[0]
    DIRECTION OUTPUT ;
    USE SIGNAL ;
    ANTENNADIFFAREA 0.360800 ;
    PORT
      LAYER Metal2 ;
        RECT 394.290 1109.000 394.670 1110.000 ;
    END
  END status_o_PD[0]
  PIN status_o_PD[1]
    DIRECTION OUTPUT ;
    USE SIGNAL ;
    ANTENNADIFFAREA 0.360800 ;
    PORT
      LAYER Metal2 ;
        RECT 494.290 1109.000 494.670 1110.000 ;
    END
  END status_o_PD[1]
  PIN status_o_PD[2]
    DIRECTION OUTPUT ;
    USE SIGNAL ;
    ANTENNADIFFAREA 0.360800 ;
    PORT
      LAYER Metal2 ;
        RECT 594.290 1109.000 594.670 1110.000 ;
    END
  END status_o_PD[2]
  PIN status_o_PD[3]
    DIRECTION OUTPUT ;
    USE SIGNAL ;
    ANTENNADIFFAREA 0.360800 ;
    PORT
      LAYER Metal2 ;
        RECT 694.290 1109.000 694.670 1110.000 ;
    END
  END status_o_PD[3]
  PIN status_o_PD[4]
    DIRECTION OUTPUT ;
    USE SIGNAL ;
    ANTENNADIFFAREA 0.360800 ;
    PORT
      LAYER Metal2 ;
        RECT 794.290 1109.000 794.670 1110.000 ;
    END
  END status_o_PD[4]
  PIN status_o_PD[5]
    DIRECTION OUTPUT ;
    USE SIGNAL ;
    ANTENNADIFFAREA 0.360800 ;
    PORT
      LAYER Metal2 ;
        RECT 894.290 1109.000 894.670 1110.000 ;
    END
  END status_o_PD[5]
  PIN status_o_PD[6]
    DIRECTION OUTPUT ;
    USE SIGNAL ;
    ANTENNADIFFAREA 0.360800 ;
    PORT
      LAYER Metal2 ;
        RECT 994.290 1109.000 994.670 1110.000 ;
    END
  END status_o_PD[6]
  PIN status_o_PU[0]
    DIRECTION OUTPUT ;
    USE SIGNAL ;
    ANTENNADIFFAREA 0.360800 ;
    PORT
      LAYER Metal2 ;
        RECT 398.655 1109.000 399.035 1110.000 ;
    END
  END status_o_PU[0]
  PIN status_o_PU[1]
    DIRECTION OUTPUT ;
    USE SIGNAL ;
    ANTENNADIFFAREA 0.360800 ;
    PORT
      LAYER Metal2 ;
        RECT 498.655 1109.000 499.035 1110.000 ;
    END
  END status_o_PU[1]
  PIN status_o_PU[2]
    DIRECTION OUTPUT ;
    USE SIGNAL ;
    ANTENNADIFFAREA 0.360800 ;
    PORT
      LAYER Metal2 ;
        RECT 598.655 1109.000 599.035 1110.000 ;
    END
  END status_o_PU[2]
  PIN status_o_PU[3]
    DIRECTION OUTPUT ;
    USE SIGNAL ;
    ANTENNADIFFAREA 0.360800 ;
    PORT
      LAYER Metal2 ;
        RECT 698.655 1109.000 699.035 1110.000 ;
    END
  END status_o_PU[3]
  PIN status_o_PU[4]
    DIRECTION OUTPUT ;
    USE SIGNAL ;
    ANTENNADIFFAREA 0.360800 ;
    PORT
      LAYER Metal2 ;
        RECT 798.655 1109.000 799.035 1110.000 ;
    END
  END status_o_PU[4]
  PIN status_o_PU[5]
    DIRECTION OUTPUT ;
    USE SIGNAL ;
    ANTENNADIFFAREA 0.360800 ;
    PORT
      LAYER Metal2 ;
        RECT 898.655 1109.000 899.035 1110.000 ;
    END
  END status_o_PU[5]
  PIN status_o_PU[6]
    DIRECTION OUTPUT ;
    USE SIGNAL ;
    ANTENNADIFFAREA 0.360800 ;
    PORT
      LAYER Metal2 ;
        RECT 998.655 1109.000 999.035 1110.000 ;
    END
  END status_o_PU[6]
  PIN status_o_SL[0]
    DIRECTION OUTPUT ;
    USE SIGNAL ;
    ANTENNADIFFAREA 0.360800 ;
    PORT
      LAYER Metal2 ;
        RECT 335.950 1109.000 336.330 1110.000 ;
    END
  END status_o_SL[0]
  PIN status_o_SL[1]
    DIRECTION OUTPUT ;
    USE SIGNAL ;
    ANTENNADIFFAREA 0.360800 ;
    PORT
      LAYER Metal2 ;
        RECT 435.950 1109.000 436.330 1110.000 ;
    END
  END status_o_SL[1]
  PIN status_o_SL[2]
    DIRECTION OUTPUT ;
    USE SIGNAL ;
    ANTENNADIFFAREA 0.360800 ;
    PORT
      LAYER Metal2 ;
        RECT 535.950 1109.000 536.330 1110.000 ;
    END
  END status_o_SL[2]
  PIN status_o_SL[3]
    DIRECTION OUTPUT ;
    USE SIGNAL ;
    ANTENNADIFFAREA 0.360800 ;
    PORT
      LAYER Metal2 ;
        RECT 635.950 1109.000 636.330 1110.000 ;
    END
  END status_o_SL[3]
  PIN status_o_SL[4]
    DIRECTION OUTPUT ;
    USE SIGNAL ;
    ANTENNADIFFAREA 0.360800 ;
    PORT
      LAYER Metal2 ;
        RECT 735.950 1109.000 736.330 1110.000 ;
    END
  END status_o_SL[4]
  PIN status_o_SL[5]
    DIRECTION OUTPUT ;
    USE SIGNAL ;
    ANTENNADIFFAREA 0.360800 ;
    PORT
      LAYER Metal2 ;
        RECT 835.950 1109.000 836.330 1110.000 ;
    END
  END status_o_SL[5]
  PIN status_o_SL[6]
    DIRECTION OUTPUT ;
    USE SIGNAL ;
    ANTENNADIFFAREA 0.360800 ;
    PORT
      LAYER Metal2 ;
        RECT 935.950 1109.000 936.330 1110.000 ;
    END
  END status_o_SL[6]
  PIN status_valid_o_CS
    DIRECTION OUTPUT ;
    USE SIGNAL ;
    ANTENNADIFFAREA 0.360800 ;
    PORT
      LAYER Metal2 ;
        RECT 301.260 1109.000 301.640 1110.000 ;
    END
  END status_valid_o_CS
  PIN status_valid_o_IE
    DIRECTION OUTPUT ;
    USE SIGNAL ;
    ANTENNADIFFAREA 0.360800 ;
    PORT
      LAYER Metal2 ;
        RECT 293.235 1109.000 293.615 1110.000 ;
    END
  END status_valid_o_IE
  PIN status_valid_o_IN
    DIRECTION INPUT ;
    USE SIGNAL ;
    PORT
      LAYER Metal2 ;
        RECT 233.760 1109.000 234.140 1110.000 ;
    END
  END status_valid_o_IN
  PIN status_valid_o_OE
    DIRECTION OUTPUT ;
    USE SIGNAL ;
    ANTENNADIFFAREA 0.536800 ;
    PORT
      LAYER Metal2 ;
        RECT 234.490 1109.000 234.870 1110.000 ;
    END
  END status_valid_o_OE
  PIN status_valid_o_OUT
    DIRECTION OUTPUT ;
    USE SIGNAL ;
    ANTENNADIFFAREA 0.897600 ;
    PORT
      LAYER Metal2 ;
        RECT 235.220 1109.000 235.600 1110.000 ;
    END
  END status_valid_o_OUT
  PIN status_valid_o_PD
    DIRECTION OUTPUT ;
    USE SIGNAL ;
    ANTENNADIFFAREA 0.360800 ;
    PORT
      LAYER Metal2 ;
        RECT 294.290 1109.000 294.670 1110.000 ;
    END
  END status_valid_o_PD
  PIN status_valid_o_PDRV0
    DIRECTION OUTPUT ;
    USE SIGNAL ;
    ANTENNADIFFAREA 0.360800 ;
    PORT
      LAYER Metal2 ;
        RECT 297.510 1109.000 297.890 1110.000 ;
    END
  END status_valid_o_PDRV0
  PIN status_valid_o_PDRV1
    DIRECTION OUTPUT ;
    USE SIGNAL ;
    ANTENNADIFFAREA 0.536800 ;
    PORT
      LAYER Metal2 ;
        RECT 296.800 1109.000 297.180 1110.000 ;
    END
  END status_valid_o_PDRV1
  PIN status_valid_o_PU
    DIRECTION OUTPUT ;
    USE SIGNAL ;
    ANTENNADIFFAREA 0.360800 ;
    PORT
      LAYER Metal2 ;
        RECT 298.655 1109.000 299.035 1110.000 ;
    END
  END status_valid_o_PU
  PIN status_valid_o_SL
    DIRECTION OUTPUT ;
    USE SIGNAL ;
    ANTENNADIFFAREA 0.360800 ;
    PORT
      LAYER Metal2 ;
        RECT 235.950 1109.000 236.330 1110.000 ;
    END
  END status_valid_o_SL
  PIN uart_rx_i
    DIRECTION INPUT ;
    USE SIGNAL ;
    ANTENNAGATEAREA 0.396000 ;
    PORT
      LAYER Metal2 ;
        RECT 0.000 508.760 1.000 509.140 ;
    END
  END uart_rx_i
  PIN uart_rx_i_PD
    DIRECTION OUTPUT ;
    USE SIGNAL ;
    ANTENNADIFFAREA 0.360800 ;
    PORT
      LAYER Metal2 ;
        RECT 0.000 569.290 1.000 569.670 ;
    END
  END uart_rx_i_PD
  PIN uart_rx_i_PU
    DIRECTION OUTPUT ;
    USE SIGNAL ;
    ANTENNADIFFAREA 0.360800 ;
    PORT
      LAYER Metal2 ;
        RECT 0.000 573.655 1.000 574.035 ;
    END
  END uart_rx_i_PU
  PIN uart_tx_o_CS
    DIRECTION OUTPUT ;
    USE SIGNAL ;
    ANTENNADIFFAREA 0.360800 ;
    PORT
      LAYER Metal2 ;
        RECT 0.000 676.260 1.000 676.640 ;
    END
  END uart_tx_o_CS
  PIN uart_tx_o_IE
    DIRECTION OUTPUT ;
    USE SIGNAL ;
    ANTENNADIFFAREA 0.360800 ;
    PORT
      LAYER Metal2 ;
        RECT 0.000 668.235 1.000 668.615 ;
    END
  END uart_tx_o_IE
  PIN uart_tx_o_IN
    DIRECTION INPUT ;
    USE SIGNAL ;
    PORT
      LAYER Metal2 ;
        RECT 0.000 608.760 1.000 609.140 ;
    END
  END uart_tx_o_IN
  PIN uart_tx_o_OE
    DIRECTION OUTPUT ;
    USE SIGNAL ;
    ANTENNADIFFAREA 0.536800 ;
    PORT
      LAYER Metal2 ;
        RECT 0.000 609.490 1.000 609.870 ;
    END
  END uart_tx_o_OE
  PIN uart_tx_o_OUT
    DIRECTION OUTPUT ;
    USE SIGNAL ;
    ANTENNADIFFAREA 0.897600 ;
    PORT
      LAYER Metal2 ;
        RECT 0.000 610.220 1.000 610.600 ;
    END
  END uart_tx_o_OUT
  PIN uart_tx_o_PD
    DIRECTION OUTPUT ;
    USE SIGNAL ;
    ANTENNADIFFAREA 0.360800 ;
    PORT
      LAYER Metal2 ;
        RECT 0.000 669.290 1.000 669.670 ;
    END
  END uart_tx_o_PD
  PIN uart_tx_o_PDRV0
    DIRECTION OUTPUT ;
    USE SIGNAL ;
    ANTENNADIFFAREA 0.360800 ;
    PORT
      LAYER Metal2 ;
        RECT 0.000 672.510 1.000 672.890 ;
    END
  END uart_tx_o_PDRV0
  PIN uart_tx_o_PDRV1
    DIRECTION OUTPUT ;
    USE SIGNAL ;
    ANTENNADIFFAREA 0.536800 ;
    PORT
      LAYER Metal2 ;
        RECT 0.000 671.800 1.000 672.180 ;
    END
  END uart_tx_o_PDRV1
  PIN uart_tx_o_PU
    DIRECTION OUTPUT ;
    USE SIGNAL ;
    ANTENNADIFFAREA 0.360800 ;
    PORT
      LAYER Metal2 ;
        RECT 0.000 673.655 1.000 674.035 ;
    END
  END uart_tx_o_PU
  PIN uart_tx_o_SL
    DIRECTION OUTPUT ;
    USE SIGNAL ;
    ANTENNADIFFAREA 0.360800 ;
    PORT
      LAYER Metal2 ;
        RECT 0.000 610.950 1.000 611.330 ;
    END
  END uart_tx_o_SL
  OBS
      LAYER Nwell ;
        RECT 15.810 19.170 1094.110 1094.110 ;
      LAYER Metal1 ;
        RECT 16.240 19.300 1093.680 1093.980 ;
      LAYER Metal2 ;
        RECT 0.140 1108.700 33.460 1109.270 ;
        RECT 36.630 1108.700 92.935 1109.270 ;
        RECT 93.915 1108.700 93.990 1109.270 ;
        RECT 94.970 1108.700 96.500 1109.270 ;
        RECT 98.190 1108.700 98.355 1109.270 ;
        RECT 99.335 1108.700 100.960 1109.270 ;
        RECT 101.940 1108.700 133.460 1109.270 ;
        RECT 136.630 1108.700 192.935 1109.270 ;
        RECT 193.915 1108.700 193.990 1109.270 ;
        RECT 194.970 1108.700 196.500 1109.270 ;
        RECT 198.190 1108.700 198.355 1109.270 ;
        RECT 199.335 1108.700 200.960 1109.270 ;
        RECT 201.940 1108.700 233.460 1109.270 ;
        RECT 236.630 1108.700 292.935 1109.270 ;
        RECT 293.915 1108.700 293.990 1109.270 ;
        RECT 294.970 1108.700 296.500 1109.270 ;
        RECT 298.190 1108.700 298.355 1109.270 ;
        RECT 299.335 1108.700 300.960 1109.270 ;
        RECT 301.940 1108.700 333.460 1109.270 ;
        RECT 336.630 1108.700 392.935 1109.270 ;
        RECT 393.915 1108.700 393.990 1109.270 ;
        RECT 394.970 1108.700 396.500 1109.270 ;
        RECT 398.190 1108.700 398.355 1109.270 ;
        RECT 399.335 1108.700 400.960 1109.270 ;
        RECT 401.940 1108.700 433.460 1109.270 ;
        RECT 436.630 1108.700 492.935 1109.270 ;
        RECT 493.915 1108.700 493.990 1109.270 ;
        RECT 494.970 1108.700 496.500 1109.270 ;
        RECT 498.190 1108.700 498.355 1109.270 ;
        RECT 499.335 1108.700 500.960 1109.270 ;
        RECT 501.940 1108.700 533.460 1109.270 ;
        RECT 536.630 1108.700 592.935 1109.270 ;
        RECT 593.915 1108.700 593.990 1109.270 ;
        RECT 594.970 1108.700 596.500 1109.270 ;
        RECT 598.190 1108.700 598.355 1109.270 ;
        RECT 599.335 1108.700 600.960 1109.270 ;
        RECT 601.940 1108.700 633.460 1109.270 ;
        RECT 636.630 1108.700 692.935 1109.270 ;
        RECT 693.915 1108.700 693.990 1109.270 ;
        RECT 694.970 1108.700 696.500 1109.270 ;
        RECT 698.190 1108.700 698.355 1109.270 ;
        RECT 699.335 1108.700 700.960 1109.270 ;
        RECT 701.940 1108.700 733.460 1109.270 ;
        RECT 736.630 1108.700 792.935 1109.270 ;
        RECT 793.915 1108.700 793.990 1109.270 ;
        RECT 794.970 1108.700 796.500 1109.270 ;
        RECT 798.190 1108.700 798.355 1109.270 ;
        RECT 799.335 1108.700 800.960 1109.270 ;
        RECT 801.940 1108.700 833.460 1109.270 ;
        RECT 836.630 1108.700 892.935 1109.270 ;
        RECT 893.915 1108.700 893.990 1109.270 ;
        RECT 894.970 1108.700 896.500 1109.270 ;
        RECT 898.190 1108.700 898.355 1109.270 ;
        RECT 899.335 1108.700 900.960 1109.270 ;
        RECT 901.940 1108.700 933.460 1109.270 ;
        RECT 936.630 1108.700 992.935 1109.270 ;
        RECT 993.915 1108.700 993.990 1109.270 ;
        RECT 994.970 1108.700 996.500 1109.270 ;
        RECT 998.190 1108.700 998.355 1109.270 ;
        RECT 999.335 1108.700 1000.960 1109.270 ;
        RECT 1001.940 1108.700 1095.780 1109.270 ;
        RECT 0.140 1076.940 1095.780 1108.700 ;
        RECT 1.300 1075.960 1095.780 1076.940 ;
        RECT 0.140 1074.335 1095.780 1075.960 ;
        RECT 1.300 1073.355 1095.780 1074.335 ;
        RECT 0.140 1073.190 1095.780 1073.355 ;
        RECT 1.300 1071.500 1095.780 1073.190 ;
        RECT 0.140 1069.970 1095.780 1071.500 ;
        RECT 1.300 1068.990 1095.780 1069.970 ;
        RECT 0.140 1068.915 1095.780 1068.990 ;
        RECT 1.300 1067.935 1095.780 1068.915 ;
        RECT 0.140 1011.630 1095.780 1067.935 ;
        RECT 1.300 1008.460 1095.780 1011.630 ;
        RECT 0.140 976.940 1095.780 1008.460 ;
        RECT 1.300 975.960 1095.780 976.940 ;
        RECT 0.140 974.335 1095.780 975.960 ;
        RECT 1.300 973.355 1095.780 974.335 ;
        RECT 0.140 973.190 1095.780 973.355 ;
        RECT 1.300 971.500 1095.780 973.190 ;
        RECT 0.140 969.970 1095.780 971.500 ;
        RECT 1.300 968.990 1095.780 969.970 ;
        RECT 0.140 968.915 1095.780 968.990 ;
        RECT 1.300 967.935 1095.780 968.915 ;
        RECT 0.140 911.630 1095.780 967.935 ;
        RECT 1.300 908.460 1095.780 911.630 ;
        RECT 0.140 876.940 1095.780 908.460 ;
        RECT 1.300 875.960 1095.780 876.940 ;
        RECT 0.140 874.335 1095.780 875.960 ;
        RECT 1.300 873.355 1095.780 874.335 ;
        RECT 0.140 873.190 1095.780 873.355 ;
        RECT 1.300 871.500 1095.780 873.190 ;
        RECT 0.140 869.970 1095.780 871.500 ;
        RECT 1.300 868.990 1095.780 869.970 ;
        RECT 0.140 868.915 1095.780 868.990 ;
        RECT 1.300 867.935 1095.780 868.915 ;
        RECT 0.140 811.630 1095.780 867.935 ;
        RECT 1.300 808.460 1095.780 811.630 ;
        RECT 0.140 776.940 1095.780 808.460 ;
        RECT 1.300 775.960 1095.780 776.940 ;
        RECT 0.140 774.335 1095.780 775.960 ;
        RECT 1.300 773.355 1095.780 774.335 ;
        RECT 0.140 773.190 1095.780 773.355 ;
        RECT 1.300 771.500 1095.780 773.190 ;
        RECT 0.140 769.970 1095.780 771.500 ;
        RECT 1.300 768.990 1095.780 769.970 ;
        RECT 0.140 768.915 1095.780 768.990 ;
        RECT 1.300 767.935 1095.780 768.915 ;
        RECT 0.140 711.630 1095.780 767.935 ;
        RECT 1.300 708.460 1095.780 711.630 ;
        RECT 0.140 676.940 1095.780 708.460 ;
        RECT 1.300 675.960 1095.780 676.940 ;
        RECT 0.140 674.335 1095.780 675.960 ;
        RECT 1.300 673.355 1095.780 674.335 ;
        RECT 0.140 673.190 1095.780 673.355 ;
        RECT 1.300 671.500 1095.780 673.190 ;
        RECT 0.140 669.970 1095.780 671.500 ;
        RECT 1.300 668.990 1095.780 669.970 ;
        RECT 0.140 668.915 1095.780 668.990 ;
        RECT 1.300 667.935 1095.780 668.915 ;
        RECT 0.140 611.630 1095.780 667.935 ;
        RECT 1.300 608.460 1095.780 611.630 ;
        RECT 0.140 574.335 1095.780 608.460 ;
        RECT 1.300 573.355 1095.780 574.335 ;
        RECT 0.140 569.970 1095.780 573.355 ;
        RECT 1.300 568.990 1095.780 569.970 ;
        RECT 0.140 509.440 1095.780 568.990 ;
        RECT 1.300 508.460 1095.780 509.440 ;
        RECT 0.140 474.335 1095.780 508.460 ;
        RECT 1.300 473.355 1095.780 474.335 ;
        RECT 0.140 469.970 1095.780 473.355 ;
        RECT 1.300 468.990 1095.780 469.970 ;
        RECT 0.140 409.440 1095.780 468.990 ;
        RECT 1.300 408.460 1095.780 409.440 ;
        RECT 0.140 374.335 1095.780 408.460 ;
        RECT 1.300 373.355 1095.780 374.335 ;
        RECT 0.140 369.970 1095.780 373.355 ;
        RECT 1.300 368.990 1095.780 369.970 ;
        RECT 0.140 309.440 1095.780 368.990 ;
        RECT 1.300 308.460 1095.780 309.440 ;
        RECT 0.140 274.335 1095.780 308.460 ;
        RECT 1.300 273.355 1095.780 274.335 ;
        RECT 0.140 269.970 1095.780 273.355 ;
        RECT 1.300 268.990 1095.780 269.970 ;
        RECT 0.140 209.440 1095.780 268.990 ;
        RECT 1.300 208.460 1095.780 209.440 ;
        RECT 0.140 174.335 1095.780 208.460 ;
        RECT 1.300 173.355 1095.780 174.335 ;
        RECT 0.140 169.970 1095.780 173.355 ;
        RECT 1.300 168.990 1095.780 169.970 ;
        RECT 0.140 109.440 1095.780 168.990 ;
        RECT 1.300 108.460 1095.780 109.440 ;
        RECT 0.140 15.770 1095.780 108.460 ;
      LAYER Metal3 ;
        RECT 0.090 15.820 1104.790 1109.220 ;
      LAYER Metal4 ;
        RECT 0.140 1103.980 1104.740 1106.470 ;
        RECT 0.140 15.770 5.940 1103.980 ;
        RECT 9.540 1098.980 29.760 1103.980 ;
        RECT 9.540 15.770 10.940 1098.980 ;
        RECT 14.540 15.770 29.760 1098.980 ;
        RECT 35.360 15.770 35.760 1103.980 ;
        RECT 41.360 15.770 104.760 1103.980 ;
        RECT 110.360 15.770 110.760 1103.980 ;
        RECT 116.360 15.770 179.760 1103.980 ;
        RECT 185.360 15.770 185.760 1103.980 ;
        RECT 191.360 15.770 254.760 1103.980 ;
        RECT 260.360 15.770 260.760 1103.980 ;
        RECT 266.360 15.770 329.760 1103.980 ;
        RECT 335.360 15.770 335.760 1103.980 ;
        RECT 341.360 15.770 404.760 1103.980 ;
        RECT 410.360 15.770 410.760 1103.980 ;
        RECT 416.360 15.770 479.760 1103.980 ;
        RECT 485.360 15.770 485.760 1103.980 ;
        RECT 491.360 15.770 554.760 1103.980 ;
        RECT 560.360 15.770 560.760 1103.980 ;
        RECT 566.360 15.770 629.760 1103.980 ;
        RECT 635.360 15.770 635.760 1103.980 ;
        RECT 641.360 15.770 704.760 1103.980 ;
        RECT 710.360 15.770 710.760 1103.980 ;
        RECT 716.360 15.770 779.760 1103.980 ;
        RECT 785.360 15.770 785.760 1103.980 ;
        RECT 791.360 15.770 854.760 1103.980 ;
        RECT 860.360 15.770 860.760 1103.980 ;
        RECT 866.360 15.770 929.760 1103.980 ;
        RECT 935.360 15.770 935.760 1103.980 ;
        RECT 941.360 15.770 1004.760 1103.980 ;
        RECT 1010.360 15.770 1010.760 1103.980 ;
        RECT 1016.360 15.770 1079.760 1103.980 ;
        RECT 1085.360 15.770 1085.760 1103.980 ;
        RECT 1091.360 1098.980 1100.380 1103.980 ;
        RECT 1091.360 15.770 1095.380 1098.980 ;
        RECT 1098.980 15.770 1100.380 1098.980 ;
        RECT 1103.980 15.770 1104.740 1103.980 ;
      LAYER Metal5 ;
        RECT 0.620 1020.350 1104.820 1082.470 ;
        RECT 0.620 1008.150 5.640 1020.350 ;
        RECT 1104.280 1008.150 1104.820 1020.350 ;
        RECT 0.620 945.350 1104.820 1008.150 ;
        RECT 0.620 933.150 5.640 945.350 ;
        RECT 1104.280 933.150 1104.820 945.350 ;
        RECT 0.620 870.350 1104.820 933.150 ;
        RECT 0.620 858.150 5.640 870.350 ;
        RECT 1104.280 858.150 1104.820 870.350 ;
        RECT 0.620 795.350 1104.820 858.150 ;
        RECT 0.620 783.150 5.640 795.350 ;
        RECT 1104.280 783.150 1104.820 795.350 ;
        RECT 0.620 720.350 1104.820 783.150 ;
        RECT 0.620 708.150 5.640 720.350 ;
        RECT 1104.280 708.150 1104.820 720.350 ;
        RECT 0.620 645.350 1104.820 708.150 ;
        RECT 0.620 633.150 5.640 645.350 ;
        RECT 1104.280 633.150 1104.820 645.350 ;
        RECT 0.620 570.350 1104.820 633.150 ;
        RECT 0.620 558.150 5.640 570.350 ;
        RECT 1104.280 558.150 1104.820 570.350 ;
        RECT 0.620 495.350 1104.820 558.150 ;
        RECT 0.620 483.150 5.640 495.350 ;
        RECT 1104.280 483.150 1104.820 495.350 ;
        RECT 0.620 420.350 1104.820 483.150 ;
        RECT 0.620 408.150 5.640 420.350 ;
        RECT 1104.280 408.150 1104.820 420.350 ;
        RECT 0.620 345.350 1104.820 408.150 ;
        RECT 0.620 333.150 5.640 345.350 ;
        RECT 1104.280 333.150 1104.820 345.350 ;
        RECT 0.620 270.350 1104.820 333.150 ;
        RECT 0.620 258.150 5.640 270.350 ;
        RECT 1104.280 258.150 1104.820 270.350 ;
        RECT 0.620 195.350 1104.820 258.150 ;
        RECT 0.620 183.150 5.640 195.350 ;
        RECT 1104.280 183.150 1104.820 195.350 ;
        RECT 0.620 120.350 1104.820 183.150 ;
        RECT 0.620 108.150 5.640 120.350 ;
        RECT 1104.280 108.150 1104.820 120.350 ;
        RECT 0.620 45.350 1104.820 108.150 ;
        RECT 0.620 33.150 5.640 45.350 ;
        RECT 1104.280 33.150 1104.820 45.350 ;
        RECT 0.620 26.330 1104.820 33.150 ;
  END
END mosaic_block_a
END LIBRARY

